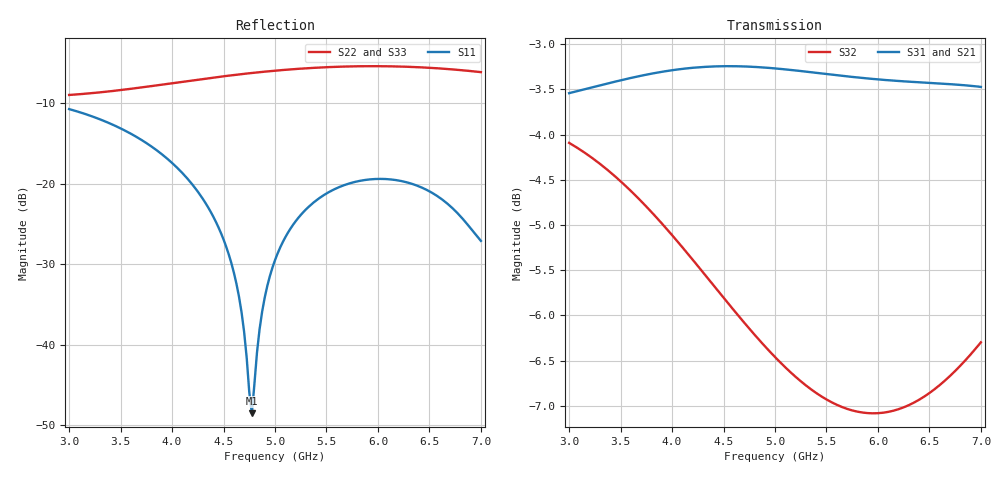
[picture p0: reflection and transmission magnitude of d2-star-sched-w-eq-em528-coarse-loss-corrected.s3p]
! yapnr Order 0 prediction d2-star-sched-w-eq-em528-coarse: predictions/D2/variants/d2-star-sched-w-eq-em528/coarse_dense.s3p, loss-corrected
! substrate W-eq-em528; coupon model OSHPARK-4L-EM528; correction: ratio (port line)
! |S21|, |S31| (and S12, S13) scaled, phases kept; 50 ohm, e^(+jwt)
# GHz S RI R 50
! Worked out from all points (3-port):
!   161 points, 3 GHz to 7 GHz, reference 50 ohm
!   strongest paths, dB at 3 GHz, 4 GHz, 5 GHz, 6 GHz, 7 GHz:
!     S31: -3.5, -3.3, -3.3, -3.4, -3.5
!     S21: -3.5, -3.3, -3.3, -3.4, -3.5
!     S32: -4.1, -5.1, -6.5, -7.1, -6.3
!   lowest |S11| = -48.5 dB at 4.775 GHz (marker M1), VSWR 1.01, Z = 49.7 + j0.257 ohm
!   |S11| at or under -10 dB: start of sweep to end of sweep
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3  -0.1102 0.2692  -0.388 -0.5407  -0.388 -0.5407
   -0.388 -0.5403  0.3139 0.168  -0.6056 -0.1519
   -0.388 -0.5403  -0.6056 -0.1519  0.3139 0.168
4.35  0.0351 0.0623  -0.6815 0.0885  -0.6815 0.0885
      -0.6824 0.0874  0.2416 -0.3819  -0.2623 0.4551
      -0.6824 0.0874  -0.2623 0.4551  0.2416 -0.3819
4.625  0.0138 0.0197  -0.6441 0.2395  -0.6441 0.2395
       -0.6457 0.2385  0.1431 -0.4534  -0.1407 0.4825
       -0.6457 0.2385  -0.1407 0.4825  0.1431 -0.4534
4.775  -0.00272 0.00259  -0.6089 0.317  -0.6089 0.317
       -0.6109 0.3162  0.0827 -0.4804  -0.0771 0.4849
       -0.6109 0.3162  -0.0771 0.4849  0.0827 -0.4804
4.875  -0.0149 -0.00598  -0.58 0.3658  -0.58 0.3658
       -0.5823 0.3652  0.0408 -0.4933  -0.0365 0.4824
       -0.5823 0.3652  -0.0365 0.4824  0.0408 -0.4933
5  -0.0307 -0.0134  -0.5384 0.4229  -0.5384 0.4229
   -0.5409 0.4227  -0.0129 -0.5035  0.012 0.4752
   -0.5409 0.4227  0.012 0.4752  -0.0129 -0.5035
5.35  -0.0725 -0.0159  -0.3935 0.5554  -0.3935 0.5554
      -0.3962 0.5565  -0.1635 -0.4972  0.1335 0.4362
      -0.3962 0.5565  0.1335 0.4362  -0.1635 -0.4972
5.925  -0.105 0.0179  -0.0962 0.6674  -0.0962 0.6674
       -0.0973 0.6705  -0.3744 -0.3854  0.2917 0.3327
       -0.0973 0.6705  0.2917 0.3327  -0.3744 -0.3854
6.5  -0.0794 0.0419  0.2212 0.6333  0.2212 0.6333
     0.2232 0.6359  -0.4895 -0.1899  0.4122 0.1903
     0.2232 0.6359  0.4122 0.1903  -0.4895 -0.1899
7  -0.0431 0.00973  0.4632 0.4817  0.4632 0.4817
   0.4665 0.4816  -0.4934 -0.00602  0.4838 0.0234
   0.4665 0.4816  0.4838 0.0234  -0.4934 -0.00602
